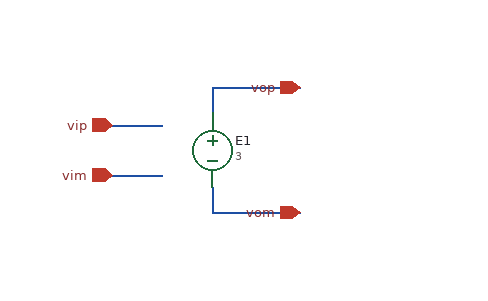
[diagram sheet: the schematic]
v {xschem version=3.4.8RC file_version=1.2}
G {}
K {}
V {}
S {}
E {}
N 0 10 -0 30 {lab=vom}
N -0 30 70 30 {lab=vom}
N 0 -70 0 -50 {lab=vop}
N 0 -70 70 -70 {lab=vop}
N -80 -40 -40 -40 {lab=vip}
N -80 -0 -40 -0 {lab=vim}
C {vcvs.sym} 0 -20 0 0 {name=E1 value=3}
C {iopin.sym} 70 30 0 0 {name=p1 lab=vom}
C {iopin.sym} 70 -70 0 0 {name=p2 lab=vop}
C {iopin.sym} -80 0 2 0 {name=p3 lab=vim}
C {iopin.sym} -80 -40 2 0 {name=p4 lab=vip}
